VERSION 5.8 ;
BUSBITCHARS "[]" ;
DIVIDERCHAR "/" ;
UNITS
    DATABASE MICRONS 1000 ;
END UNITS

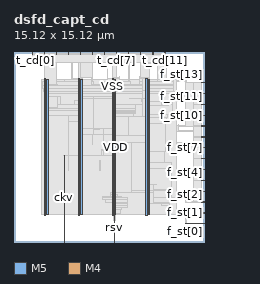
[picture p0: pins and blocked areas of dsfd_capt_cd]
MACRO dsfd_capt_cd
  FOREIGN dsfd_capt_cd 0 0 ;
  CLASS BLOCK ;
  SIZE 15.12 BY 15.12 ;
  PIN ckv
    DIRECTION INPUT ;
    USE SIGNAL ;
    PORT
      LAYER M5 ;
        RECT  3.984 0 4.008 0.192 ;
    END
    PORT
      LAYER M5 ;
        RECT  3.984 0.144 4.008 6.899 ;
    END
  END ckv
  PIN f_st[0]
    DIRECTION INPUT ;
    USE SIGNAL ;
    PORT
      LAYER M4 ;
        RECT  14.928 1.44 15.12 1.464 ;
    END
    PORT
      LAYER M4 ;
        RECT  13.669 1.44 14.94 1.464 ;
    END
  END f_st[0]
  PIN f_st[10]
    DIRECTION INPUT ;
    USE SIGNAL ;
    PORT
      LAYER M4 ;
        RECT  14.928 10.08 15.12 10.104 ;
    END
  END f_st[10]
  PIN f_st[11]
    DIRECTION INPUT ;
    USE SIGNAL ;
    PORT
      LAYER M4 ;
        RECT  14.928 10.944 15.12 10.968 ;
    END
  END f_st[11]
  PIN f_st[12]
    DIRECTION INPUT ;
    USE SIGNAL ;
    PORT
      LAYER M4 ;
        RECT  14.928 11.808 15.12 11.832 ;
    END
  END f_st[12]
  PIN f_st[13]
    DIRECTION INPUT ;
    USE SIGNAL ;
    PORT
      LAYER M4 ;
        RECT  14.928 12.672 15.12 12.696 ;
    END
  END f_st[13]
  PIN f_st[1]
    DIRECTION INPUT ;
    USE SIGNAL ;
    PORT
      LAYER M4 ;
        RECT  14.928 2.304 15.12 2.328 ;
    END
  END f_st[1]
  PIN f_st[2]
    DIRECTION INPUT ;
    USE SIGNAL ;
    PORT
      LAYER M4 ;
        RECT  14.928 3.168 15.12 3.192 ;
    END
  END f_st[2]
  PIN f_st[3]
    DIRECTION INPUT ;
    USE SIGNAL ;
    PORT
      LAYER M4 ;
        RECT  14.928 4.032 15.12 4.056 ;
    END
  END f_st[3]
  PIN f_st[4]
    DIRECTION INPUT ;
    USE SIGNAL ;
    PORT
      LAYER M4 ;
        RECT  14.928 4.896 15.12 4.92 ;
    END
  END f_st[4]
  PIN f_st[5]
    DIRECTION INPUT ;
    USE SIGNAL ;
    PORT
      LAYER M4 ;
        RECT  14.928 5.76 15.12 5.784 ;
    END
  END f_st[5]
  PIN f_st[6]
    DIRECTION INPUT ;
    USE SIGNAL ;
    PORT
      LAYER M4 ;
        RECT  14.928 6.624 15.12 6.648 ;
    END
  END f_st[6]
  PIN f_st[7]
    DIRECTION INPUT ;
    USE SIGNAL ;
    PORT
      LAYER M4 ;
        RECT  14.928 7.488 15.12 7.512 ;
    END
  END f_st[7]
  PIN f_st[8]
    DIRECTION INPUT ;
    USE SIGNAL ;
    PORT
      LAYER M4 ;
        RECT  14.928 8.352 15.12 8.376 ;
    END
  END f_st[8]
  PIN f_st[9]
    DIRECTION INPUT ;
    USE SIGNAL ;
    PORT
      LAYER M4 ;
        RECT  14.928 9.216 15.12 9.24 ;
    END
  END f_st[9]
  PIN rsv
    DIRECTION INPUT ;
    USE SIGNAL ;
    PORT
      LAYER M5 ;
        RECT  7.968 0 7.992 0.192 ;
    END
    PORT
      LAYER M5 ;
        RECT  7.968 0.144 7.992 2.137 ;
    END
  END rsv
  PIN t_cd[0]
    DIRECTION OUTPUT ;
    USE SIGNAL ;
    PORT
      LAYER M5 ;
        RECT  1.44 14.928 1.464 15.12 ;
    END
  END t_cd[0]
  PIN t_cd[10]
    DIRECTION OUTPUT ;
    USE SIGNAL ;
    PORT
      LAYER M5 ;
        RECT  11.04 14.928 11.064 15.12 ;
    END
  END t_cd[10]
  PIN t_cd[11]
    DIRECTION OUTPUT ;
    USE SIGNAL ;
    PORT
      LAYER M5 ;
        RECT  12 14.928 12.024 15.12 ;
    END
  END t_cd[11]
  PIN t_cd[1]
    DIRECTION OUTPUT ;
    USE SIGNAL ;
    PORT
      LAYER M5 ;
        RECT  2.4 14.928 2.424 15.12 ;
    END
  END t_cd[1]
  PIN t_cd[2]
    DIRECTION OUTPUT ;
    USE SIGNAL ;
    PORT
      LAYER M5 ;
        RECT  3.36 14.928 3.384 15.12 ;
    END
  END t_cd[2]
  PIN t_cd[3]
    DIRECTION OUTPUT ;
    USE SIGNAL ;
    PORT
      LAYER M5 ;
        RECT  4.32 14.928 4.344 15.12 ;
    END
  END t_cd[3]
  PIN t_cd[4]
    DIRECTION OUTPUT ;
    USE SIGNAL ;
    PORT
      LAYER M5 ;
        RECT  5.28 14.928 5.304 15.12 ;
    END
  END t_cd[4]
  PIN t_cd[5]
    DIRECTION OUTPUT ;
    USE SIGNAL ;
    PORT
      LAYER M5 ;
        RECT  6.24 14.928 6.264 15.12 ;
    END
  END t_cd[5]
  PIN t_cd[6]
    DIRECTION OUTPUT ;
    USE SIGNAL ;
    PORT
      LAYER M5 ;
        RECT  7.2 14.928 7.224 15.12 ;
    END
  END t_cd[6]
  PIN t_cd[7]
    DIRECTION OUTPUT ;
    USE SIGNAL ;
    PORT
      LAYER M5 ;
        RECT  8.16 14.928 8.184 15.12 ;
    END
  END t_cd[7]
  PIN t_cd[8]
    DIRECTION OUTPUT ;
    USE SIGNAL ;
    PORT
      LAYER M5 ;
        RECT  9.12 14.928 9.144 15.12 ;
    END
  END t_cd[8]
  PIN t_cd[9]
    DIRECTION OUTPUT ;
    USE SIGNAL ;
    PORT
      LAYER M5 ;
        RECT  10.08 14.928 10.104 15.12 ;
    END
  END t_cd[9]
  PIN VDD
    DIRECTION INOUT ;
    USE POWER ;
    PORT
      LAYER M5 ;
        RECT  10.692 2.151 10.812 12.969 ;
        RECT  7.992 2.151 8.112 12.969 ;
        RECT  5.292 2.151 5.412 12.969 ;
        RECT  2.592 2.151 2.712 12.969 ;
    END
  END VDD
  PIN VSS
    DIRECTION INOUT ;
    USE GROUND ;
    PORT
      LAYER M5 ;
        RECT  10.5 2.137 10.62 12.983 ;
        RECT  7.8 2.137 7.92 12.983 ;
        RECT  5.1 2.137 5.22 12.983 ;
        RECT  2.4 2.137 2.52 12.983 ;
    END
  END VSS
  # OT_OBS_CLOSED layer=M5 d_um=1.536 added=16
  OBS
    LAYER RVTN ;
     RECT  2.16 2.16 12.96 2.295 ;
     RECT  2.16 2.565 12.96 2.835 ;
     RECT  2.16 3.105 12.96 3.375 ;
     RECT  2.16 3.645 12.96 3.915 ;
     RECT  2.16 4.185 12.96 4.455 ;
     RECT  2.16 4.725 12.96 4.995 ;
     RECT  2.16 5.265 12.96 5.535 ;
     RECT  2.16 5.805 12.96 6.075 ;
     RECT  2.16 6.345 12.96 6.615 ;
     RECT  2.16 6.885 12.96 7.155 ;
     RECT  2.16 7.425 12.96 7.695 ;
     RECT  2.16 7.965 12.96 8.235 ;
     RECT  2.16 8.505 12.96 8.775 ;
     RECT  2.16 9.045 12.96 9.315 ;
     RECT  2.16 9.585 12.96 9.855 ;
     RECT  2.16 10.125 12.96 10.395 ;
     RECT  2.16 10.665 12.96 10.935 ;
     RECT  2.16 11.205 12.96 11.475 ;
     RECT  2.16 11.745 12.96 12.015 ;
     RECT  2.16 12.285 12.96 12.555 ;
     RECT  2.16 12.825 12.96 12.96 ;
    LAYER RVTP ;
     RECT  2.16 2.295 12.96 2.565 ;
     RECT  2.16 2.835 12.96 3.105 ;
     RECT  2.16 3.375 12.96 3.645 ;
     RECT  2.16 3.915 12.96 4.185 ;
     RECT  2.16 4.455 12.96 4.725 ;
     RECT  2.16 4.995 12.96 5.265 ;
     RECT  2.16 5.535 12.96 5.805 ;
     RECT  2.16 6.075 12.96 6.345 ;
     RECT  2.16 6.615 12.96 6.885 ;
     RECT  2.16 7.155 12.96 7.425 ;
     RECT  2.16 7.695 12.96 7.965 ;
     RECT  2.16 8.235 12.96 8.505 ;
     RECT  2.16 8.775 12.96 9.045 ;
     RECT  2.16 9.315 12.96 9.585 ;
     RECT  2.16 9.855 12.96 10.125 ;
     RECT  2.16 10.395 12.96 10.665 ;
     RECT  2.16 10.935 12.96 11.205 ;
     RECT  2.16 11.475 12.96 11.745 ;
     RECT  2.16 12.015 12.96 12.285 ;
     RECT  2.16 12.555 12.96 12.825 ;
    LAYER M1 ;
     RECT  2.16 2.151 12.96 12.969 ;
    LAYER M2 ;
     RECT  2.16 2.151 12.96 12.969 ;
     RECT  12.96 8.82 13.127 9.306 ;
     RECT  12.96 2.268 13.703 2.286 ;
     RECT  12.96 3.618 13.703 3.978 ;
     RECT  12.96 5.58 13.703 5.796 ;
     RECT  12.96 10.368 13.703 10.386 ;
     RECT  12.96 11.178 13.703 11.844 ;
     RECT  12.96 12.798 13.703 12.816 ;
     RECT  13.703 3.96 14.279 3.978 ;
     RECT  13.703 5.58 14.279 5.598 ;
     RECT  12.96 7.2 14.279 7.956 ;
     RECT  13.127 8.82 14.279 8.838 ;
    LAYER M3 ;
     RECT  8.028 1.723 8.046 2.143 ;
     RECT  7.815 2.143 8.046 2.263 ;
     RECT  13.68 1.435 13.698 2.291 ;
     RECT  2.415 2.143 2.505 2.413 ;
     RECT  5.115 2.143 5.205 2.413 ;
     RECT  10.515 2.143 10.605 2.413 ;
     RECT  7.815 2.263 8.514 2.605 ;
     RECT  7.815 2.605 8.55 2.767 ;
     RECT  7.815 2.767 9.018 2.911 ;
     RECT  12.348 2.371 12.366 2.911 ;
     RECT  7.815 2.911 9.054 3.029 ;
     RECT  10.515 2.413 10.797 3.037 ;
     RECT  10.515 3.037 10.962 3.073 ;
     RECT  11.772 2.911 12.366 3.073 ;
     RECT  10.515 3.073 12.366 3.109 ;
     RECT  7.815 3.029 9.018 3.145 ;
     RECT  7.272 3.145 9.018 3.415 ;
     RECT  7.056 3.415 9.018 3.569 ;
     RECT  10.515 3.109 12.762 3.569 ;
     RECT  7.056 3.569 8.55 3.605 ;
     RECT  7.704 3.605 8.514 3.641 ;
     RECT  13.68 3.163 13.698 3.641 ;
     RECT  7.704 3.641 8.262 3.749 ;
     RECT  7.704 3.749 8.097 3.965 ;
     RECT  14.256 3.955 14.274 4.061 ;
     RECT  10.515 3.569 12.51 4.075 ;
     RECT  10.44 4.075 12.51 4.145 ;
     RECT  14.256 4.891 14.274 5.603 ;
     RECT  13.68 5.755 13.698 5.801 ;
     RECT  10.515 4.145 12.51 5.881 ;
     RECT  4.32 5.701 4.338 6.277 ;
     RECT  10.515 5.881 12.546 6.341 ;
     RECT  6.84 5.701 6.858 6.449 ;
     RECT  10.515 6.341 11.97 7.231 ;
     RECT  6.948 6.859 6.966 7.321 ;
     RECT  7.815 3.965 8.097 7.321 ;
     RECT  6.948 7.321 8.097 7.373 ;
     RECT  6.948 7.373 6.966 7.385 ;
     RECT  8.928 7.867 9.162 8.195 ;
     RECT  9.144 8.195 9.162 8.525 ;
     RECT  5.115 2.413 5.397 8.539 ;
     RECT  6.228 7.735 6.246 8.539 ;
     RECT  14.256 6.619 14.274 8.843 ;
     RECT  5.115 8.539 6.246 8.977 ;
     RECT  5.115 8.977 6.786 9.005 ;
     RECT  6.156 9.005 6.786 9.101 ;
     RECT  13.104 9.211 13.122 9.311 ;
     RECT  10.515 7.231 12.042 9.391 ;
     RECT  4.32 6.277 4.374 9.625 ;
     RECT  5.115 9.005 5.397 9.625 ;
     RECT  10.515 9.391 12.114 9.931 ;
     RECT  7.815 7.373 8.097 9.979 ;
     RECT  9.108 9.859 9.486 9.979 ;
     RECT  2.415 2.413 2.697 10.057 ;
     RECT  2.415 10.057 3.402 10.093 ;
     RECT  4.32 9.625 5.397 10.093 ;
     RECT  10.515 9.931 12.222 10.129 ;
     RECT  7.815 9.979 9.486 10.201 ;
     RECT  7.815 10.201 9.702 10.327 ;
     RECT  7.668 10.327 9.702 10.399 ;
     RECT  2.415 10.093 5.397 10.435 ;
     RECT  6.228 9.101 6.786 10.435 ;
     RECT  7.632 10.399 9.702 10.471 ;
     RECT  2.415 10.435 6.786 10.597 ;
     RECT  7.596 10.471 9.702 10.597 ;
     RECT  2.415 10.597 9.702 10.975 ;
     RECT  10.515 10.129 12.582 10.975 ;
     RECT  2.415 10.975 12.618 11.785 ;
     RECT  13.68 10.075 13.698 11.849 ;
     RECT  2.415 11.785 12.762 11.939 ;
     RECT  2.415 11.939 12.654 11.947 ;
     RECT  2.376 11.947 12.654 12.181 ;
     RECT  2.304 12.181 12.654 12.479 ;
     RECT  6.192 12.479 12.654 12.551 ;
     RECT  2.304 12.479 5.454 12.749 ;
     RECT  6.192 12.551 6.318 12.749 ;
     RECT  7.2 12.551 9.234 12.749 ;
     RECT  7.416 12.749 8.406 12.785 ;
     RECT  10.008 12.551 12.654 12.785 ;
     RECT  13.68 12.667 13.698 12.821 ;
     RECT  3.996 12.749 5.454 12.893 ;
     RECT  11.448 12.785 12.654 12.893 ;
     RECT  6.192 12.749 6.282 12.929 ;
     RECT  2.415 12.749 2.79 12.977 ;
     RECT  4.608 12.893 5.454 12.977 ;
     RECT  7.452 12.785 8.406 12.977 ;
     RECT  10.008 12.785 10.605 12.977 ;
     RECT  2.736 12.977 2.79 13.133 ;
     RECT  6.192 12.929 6.21 13.133 ;
     RECT  8.388 12.977 8.406 13.133 ;
     RECT  10.008 12.977 10.026 13.133 ;
     RECT  5.436 12.977 5.454 13.661 ;
     RECT  11.448 12.893 12.15 14.237 ;
     RECT  2.736 13.133 2.754 14.285 ;
     RECT  4.608 12.977 4.626 14.285 ;
     RECT  7.452 12.977 7.47 14.285 ;
     RECT  9.144 12.749 9.162 14.285 ;
     RECT  11.448 14.237 11.466 14.285 ;
    LAYER M4 ;
     RECT  2.389 13.104 2.408 13.128 ;
     RECT  2.408 2.148 2.512 13.128 ;
     RECT  2.512 2.418 2.704 13.128 ;
     RECT  1.429 14.256 2.765 14.28 ;
     RECT  2.704 12.528 2.801 13.128 ;
     RECT  2.801 12.528 3.436 12.552 ;
     RECT  2.704 10.704 3.449 11.544 ;
     RECT  3.449 10.944 3.701 11.544 ;
     RECT  4.309 14.256 4.637 14.28 ;
     RECT  3.701 10.944 4.813 10.968 ;
     RECT  3.973 6.864 5.108 6.888 ;
     RECT  4.813 10.944 5.108 11.256 ;
     RECT  5.108 2.148 5.212 12.972 ;
     RECT  5.212 2.418 5.269 12.972 ;
     RECT  5.269 2.418 5.404 13.656 ;
     RECT  5.404 13.104 5.465 13.656 ;
     RECT  5.465 13.104 6.275 13.128 ;
     RECT  5.404 8.544 6.323 9.096 ;
     RECT  5.404 10.56 6.365 11.544 ;
     RECT  5.404 6.864 7.1 6.888 ;
     RECT  7.1 6.864 7.141 7.368 ;
     RECT  6.323 8.544 7.141 8.568 ;
     RECT  7.189 14.256 7.481 14.28 ;
     RECT  7.693 3.936 7.808 3.96 ;
     RECT  7.141 6.864 7.808 8.568 ;
     RECT  6.365 10.656 7.808 11.544 ;
     RECT  7.808 2.148 7.957 12.972 ;
     RECT  7.957 1.728 8.057 12.972 ;
     RECT  8.057 2.418 8.104 12.972 ;
     RECT  8.149 13.104 8.417 13.128 ;
     RECT  8.104 7.872 9.089 7.992 ;
     RECT  9.089 7.872 9.173 8.52 ;
     RECT  9.109 14.256 9.196 14.28 ;
     RECT  9.173 7.872 9.395 7.896 ;
     RECT  8.104 3.936 9.637 3.96 ;
     RECT  9.997 13.104 10.115 13.128 ;
     RECT  9.205 11.424 10.141 11.448 ;
     RECT  10.141 11.184 10.213 11.448 ;
     RECT  9.637 3.936 10.508 4.104 ;
     RECT  8.104 9.984 10.508 10.008 ;
     RECT  10.213 11.184 10.508 12.024 ;
     RECT  10.508 2.148 10.612 12.972 ;
     RECT  10.612 2.418 10.804 12.702 ;
     RECT  10.804 3.072 11.075 3.096 ;
     RECT  10.804 4.128 11.075 4.584 ;
     RECT  11.075 4.56 11.333 4.584 ;
     RECT  11.029 14.256 11.477 14.28 ;
     RECT  10.804 10.896 11.765 11.208 ;
     RECT  11.989 14.208 12.161 14.232 ;
     RECT  11.765 10.896 12.269 10.92 ;
     RECT  13.093 9.216 13.669 9.24 ;
     RECT  13.669 3.168 14.245 3.192 ;
     RECT  13.669 5.76 14.245 5.784 ;
     RECT  13.669 9.216 14.245 12.696 ;
     RECT  14.245 3.168 14.928 3.192 ;
     RECT  14.245 3.192 14.94 4.032 ;
     RECT  14.245 4.032 14.928 4.056 ;
     RECT  14.245 4.056 14.94 4.896 ;
     RECT  14.245 4.896 14.928 4.92 ;
     RECT  14.245 4.92 14.94 5.76 ;
     RECT  14.245 5.76 14.928 5.784 ;
     RECT  14.245 5.784 14.94 6.624 ;
     RECT  14.245 6.624 14.928 6.648 ;
     RECT  14.245 6.648 14.94 7.488 ;
     RECT  14.245 7.488 14.928 7.512 ;
     RECT  14.245 7.512 14.94 8.352 ;
     RECT  14.245 8.352 14.928 8.376 ;
     RECT  14.245 8.376 14.94 9.216 ;
     RECT  14.245 9.216 14.928 9.24 ;
     RECT  14.245 9.24 14.94 10.08 ;
     RECT  14.245 10.08 14.928 10.104 ;
     RECT  14.245 10.104 14.94 10.944 ;
     RECT  14.245 10.944 14.928 10.968 ;
     RECT  14.245 10.968 14.94 11.808 ;
     RECT  14.245 11.808 14.928 11.832 ;
     RECT  14.245 11.832 14.94 12.672 ;
     RECT  14.245 12.672 14.928 12.696 ;
    LAYER M5 ;
     RECT  2.4 2.137 2.52 2.151 ;
     RECT  5.1 2.137 5.22 2.151 ;
     RECT  7.8 2.137 7.992 2.151 ;
     RECT  10.5 2.137 10.62 2.151 ;
     RECT  10.5 2.151 10.812 3.061 ;
     RECT  10.5 3.061 11.064 3.925 ;
     RECT  9.36 3.925 11.064 4.115 ;
     RECT  10.5 4.115 11.064 4.595 ;
     RECT  7.8 2.151 8.112 7.333 ;
     RECT  9.36 4.115 9.384 7.907 ;
     RECT  7.152 7.333 8.112 8.579 ;
     RECT  5.1 2.151 5.412 9.061 ;
     RECT  9.12 8.485 9.144 10.019 ;
     RECT  10.5 4.595 10.812 11.413 ;
     RECT  5.1 9.061 6.312 11.459 ;
     RECT  10.224 11.413 10.812 12.035 ;
     RECT  2.4 2.151 2.712 12.517 ;
     RECT  10.5 12.035 10.812 12.969 ;
     RECT  5.1 11.459 5.412 12.983 ;
     RECT  7.8 8.579 8.112 12.983 ;
     RECT  10.5 12.969 10.62 12.983 ;
     RECT  5.28 12.983 5.412 13.093 ;
     RECT  2.4 12.517 3.384 14.245 ;
     RECT  5.28 13.093 6.264 14.245 ;
     RECT  8.16 13.093 8.184 14.245 ;
     RECT  10.08 13.093 10.104 14.245 ;
     RECT  12 14.197 12.024 14.245 ;
     RECT  1.44 14.245 12.024 14.928 ;
     RECT  1.464 14.928 2.4 14.992 ;
     RECT  2.424 14.928 3.36 14.992 ;
     RECT  3.384 14.928 4.32 14.992 ;
     RECT  4.344 14.928 5.28 14.992 ;
     RECT  5.304 14.928 6.24 14.992 ;
     RECT  6.264 14.928 7.2 14.992 ;
     RECT  7.224 14.928 8.16 14.992 ;
     RECT  8.184 14.928 9.12 14.992 ;
     RECT  9.144 14.928 10.08 14.992 ;
     RECT  10.104 14.928 11.04 14.992 ;
     RECT  11.064 14.928 12 14.992 ;
     RECT  8.112 3.925 9.36 7.907 ;
     RECT  9.384 4.115 10.5 7.907 ;
     RECT  8.112 7.907 10.5 8.485 ;
     RECT  8.112 8.485 9.12 10.019 ;
     RECT  9.144 8.485 10.5 10.019 ;
     RECT  7.152 8.579 7.8 9.061 ;
     RECT  6.312 9.061 7.8 11.459 ;
     RECT  10.224 10.019 10.5 11.413 ;
     RECT  10.224 12.035 10.5 12.983 ;
     RECT  10.62 12.969 10.812 12.983 ;
     RECT  5.1 12.983 5.28 14.245 ;
     RECT  7.8 12.983 8.112 13.093 ;
     RECT  10.224 12.983 10.812 13.093 ;
     RECT  7.8 13.093 8.16 14.245 ;
     RECT  10.104 13.093 10.812 14.197 ;
     RECT  10.104 14.197 12 14.245 ;
  END
END dsfd_capt_cd
END LIBRARY
